VERSION 5.7 ;
  NOWIREEXTENSIONATPIN ON ;
  DIVIDERCHAR "/" ;
  BUSBITCHARS "[]" ;
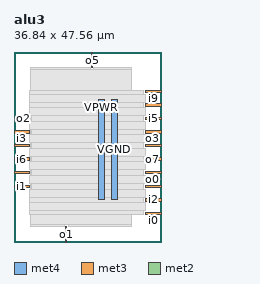
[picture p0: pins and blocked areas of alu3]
MACRO alu3
  CLASS BLOCK ;
  FOREIGN alu3 ;
  ORIGIN 0.000 0.000 ;
  SIZE 36.840 BY 47.560 ;
  PIN VGND
    DIRECTION INOUT ;
    USE GROUND ;
    PORT
      LAYER met4 ;
        RECT 24.340 10.640 25.940 35.600 ;
    END
  END VGND
  PIN VPWR
    DIRECTION INOUT ;
    USE POWER ;
    PORT
      LAYER met4 ;
        RECT 21.040 10.640 22.640 35.600 ;
    END
  END VPWR
  PIN i0
    DIRECTION INPUT ;
    USE SIGNAL ;
    ANTENNAGATEAREA 0.213000 ;
    PORT
      LAYER met3 ;
        RECT 32.840 6.840 36.840 7.440 ;
    END
  END i0
  PIN i1
    DIRECTION INPUT ;
    USE SIGNAL ;
    ANTENNAGATEAREA 0.213000 ;
    PORT
      LAYER met3 ;
        RECT 0.000 13.640 4.000 14.240 ;
    END
  END i1
  PIN i2
    DIRECTION INPUT ;
    USE SIGNAL ;
    ANTENNAGATEAREA 0.213000 ;
    PORT
      LAYER met3 ;
        RECT 32.840 10.240 36.840 10.840 ;
    END
  END i2
  PIN i3
    DIRECTION INPUT ;
    USE SIGNAL ;
    ANTENNAGATEAREA 0.213000 ;
    PORT
      LAYER met3 ;
        RECT 0.000 23.840 4.000 24.440 ;
    END
  END i3
  PIN i4
    DIRECTION INPUT ;
    USE SIGNAL ;
    ANTENNAGATEAREA 0.213000 ;
    PORT
      LAYER met3 ;
        RECT 32.840 17.040 36.840 17.640 ;
    END
  END i4
  PIN i5
    DIRECTION INPUT ;
    USE SIGNAL ;
    ANTENNAGATEAREA 0.196500 ;
    PORT
      LAYER met3 ;
        RECT 32.840 30.640 36.840 31.240 ;
    END
  END i5
  PIN i6
    DIRECTION INPUT ;
    USE SIGNAL ;
    ANTENNAGATEAREA 0.126000 ;
    PORT
      LAYER met3 ;
        RECT 0.000 20.440 4.000 21.040 ;
    END
  END i6
  PIN i7
    DIRECTION INPUT ;
    USE SIGNAL ;
    ANTENNAGATEAREA 0.196500 ;
    PORT
      LAYER met3 ;
        RECT 0.000 17.040 4.000 17.640 ;
    END
  END i7
  PIN i8
    DIRECTION INPUT ;
    USE SIGNAL ;
    ANTENNAGATEAREA 0.213000 ;
    PORT
      LAYER met3 ;
        RECT 0.000 27.240 4.000 27.840 ;
    END
  END i8
  PIN i9
    DIRECTION INPUT ;
    USE SIGNAL ;
    ANTENNAGATEAREA 0.196500 ;
    PORT
      LAYER met3 ;
        RECT 32.840 34.040 36.840 34.640 ;
    END
  END i9
  PIN o0
    DIRECTION OUTPUT ;
    USE SIGNAL ;
    ANTENNADIFFAREA 0.445500 ;
    PORT
      LAYER met3 ;
        RECT 32.840 13.640 36.840 14.240 ;
    END
  END o0
  PIN o1
    DIRECTION OUTPUT ;
    USE SIGNAL ;
    ANTENNADIFFAREA 0.445500 ;
    PORT
      LAYER met2 ;
        RECT 12.970 0.000 13.250 4.000 ;
    END
  END o1
  PIN o2
    DIRECTION OUTPUT ;
    USE SIGNAL ;
    ANTENNADIFFAREA 0.445500 ;
    PORT
      LAYER met3 ;
        RECT 0.000 30.640 4.000 31.240 ;
    END
  END o2
  PIN o3
    DIRECTION OUTPUT ;
    USE SIGNAL ;
    ANTENNADIFFAREA 0.445500 ;
    PORT
      LAYER met3 ;
        RECT 32.840 27.240 36.840 27.840 ;
    END
  END o3
  PIN o4
    DIRECTION OUTPUT ;
    USE SIGNAL ;
    ANTENNADIFFAREA 0.445500 ;
    PORT
      LAYER met3 ;
        RECT 32.840 37.440 36.840 38.040 ;
    END
  END o4
  PIN o5
    DIRECTION OUTPUT ;
    USE SIGNAL ;
    ANTENNADIFFAREA 0.445500 ;
    PORT
      LAYER met2 ;
        RECT 19.410 43.560 19.690 47.560 ;
    END
  END o5
  PIN o6
    DIRECTION OUTPUT ;
    USE SIGNAL ;
    ANTENNADIFFAREA 0.445500 ;
    PORT
      LAYER met3 ;
        RECT 32.840 23.840 36.840 24.440 ;
    END
  END o6
  PIN o7
    DIRECTION OUTPUT ;
    USE SIGNAL ;
    ANTENNADIFFAREA 0.445500 ;
    PORT
      LAYER met3 ;
        RECT 32.840 20.440 36.840 21.040 ;
    END
  END o7
  OBS
      LAYER nwell ;
        RECT 5.330 10.795 31.470 35.550 ;
      LAYER li1 ;
        RECT 5.520 10.795 31.280 35.445 ;
      LAYER met1 ;
        RECT 4.210 10.640 31.280 35.600 ;
      LAYER met2 ;
        RECT 4.230 43.280 19.130 43.560 ;
        RECT 19.970 43.280 29.350 43.560 ;
        RECT 4.230 4.280 29.350 43.280 ;
        RECT 4.230 4.000 12.690 4.280 ;
        RECT 13.530 4.000 29.350 4.280 ;
      LAYER met3 ;
        RECT 3.990 37.040 32.440 37.905 ;
        RECT 3.990 35.040 32.840 37.040 ;
        RECT 3.990 33.640 32.440 35.040 ;
        RECT 3.990 31.640 32.840 33.640 ;
        RECT 4.400 30.240 32.440 31.640 ;
        RECT 3.990 28.240 32.840 30.240 ;
        RECT 4.400 26.840 32.440 28.240 ;
        RECT 3.990 24.840 32.840 26.840 ;
        RECT 4.400 23.440 32.440 24.840 ;
        RECT 3.990 21.440 32.840 23.440 ;
        RECT 4.400 20.040 32.440 21.440 ;
        RECT 3.990 18.040 32.840 20.040 ;
        RECT 4.400 16.640 32.440 18.040 ;
        RECT 3.990 14.640 32.840 16.640 ;
        RECT 4.400 13.240 32.440 14.640 ;
        RECT 3.990 11.240 32.840 13.240 ;
        RECT 3.990 9.840 32.440 11.240 ;
        RECT 3.990 7.840 32.840 9.840 ;
        RECT 3.990 6.975 32.440 7.840 ;
  END
END alu3
END LIBRARY

